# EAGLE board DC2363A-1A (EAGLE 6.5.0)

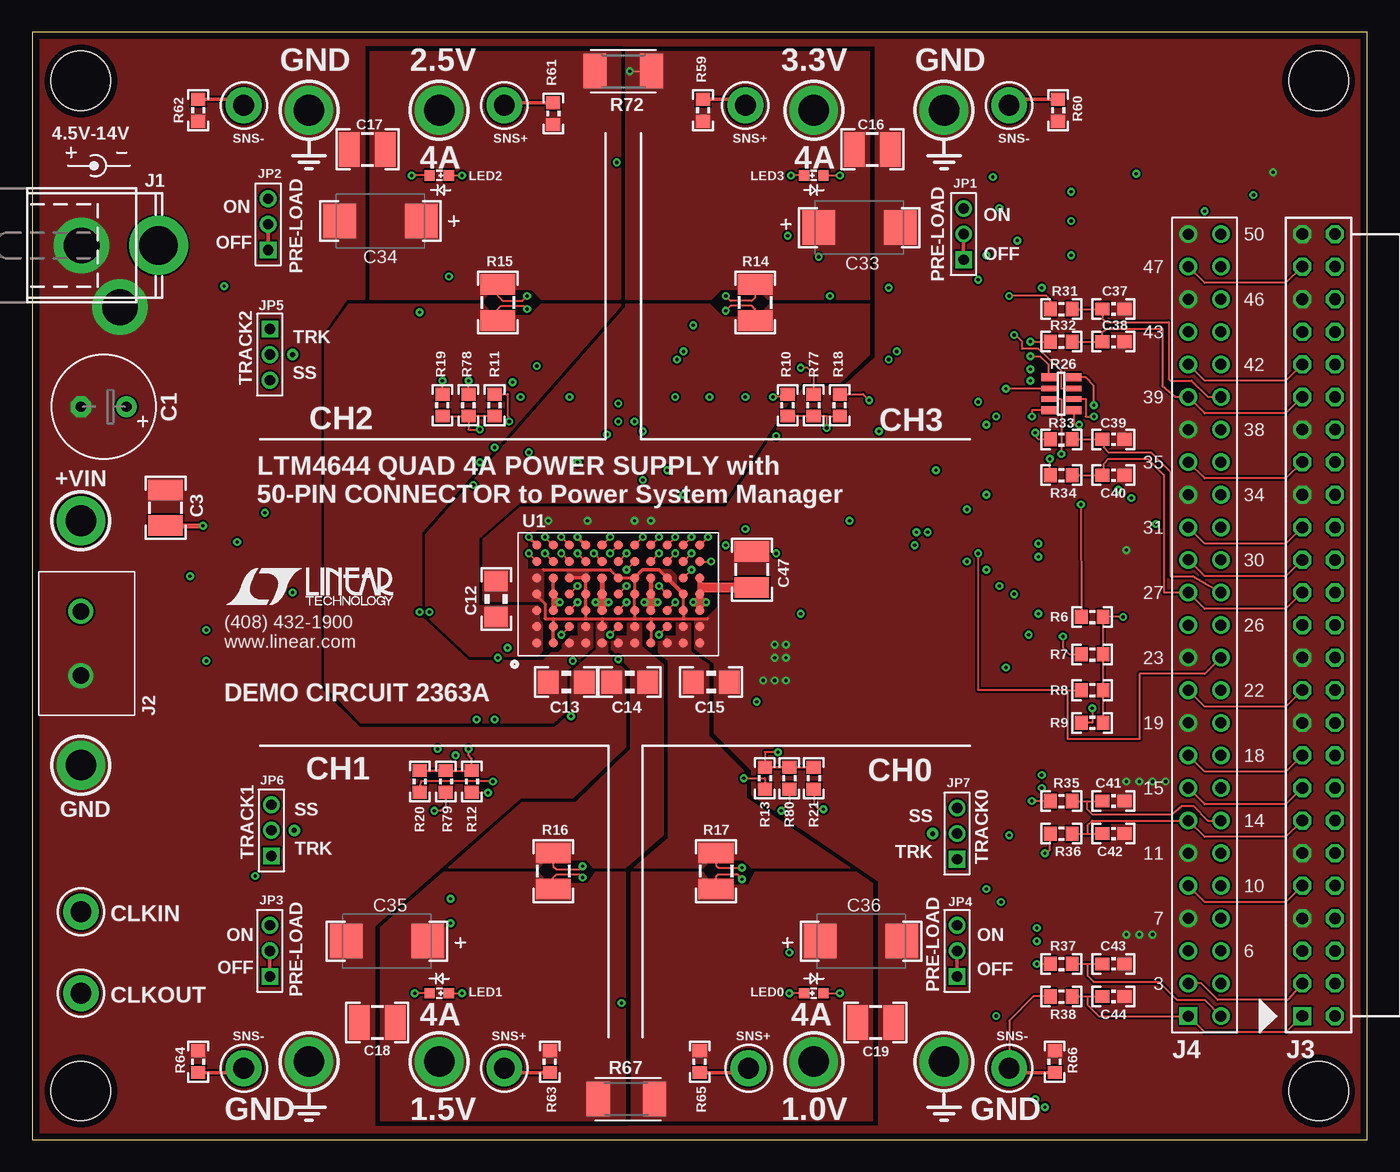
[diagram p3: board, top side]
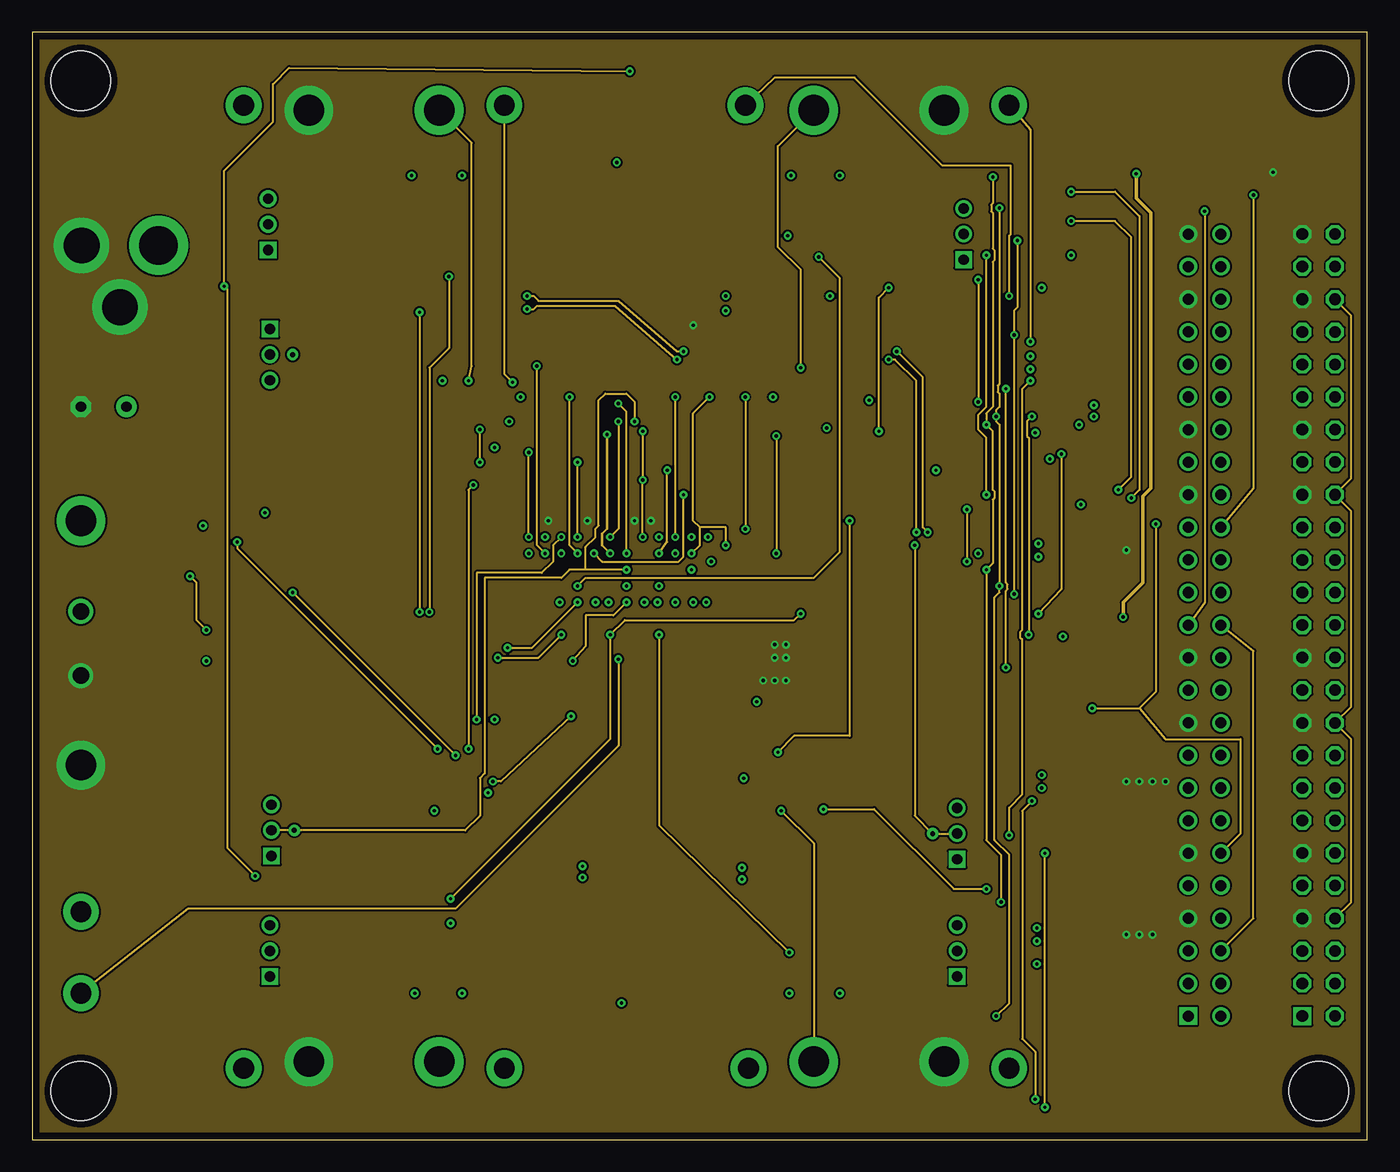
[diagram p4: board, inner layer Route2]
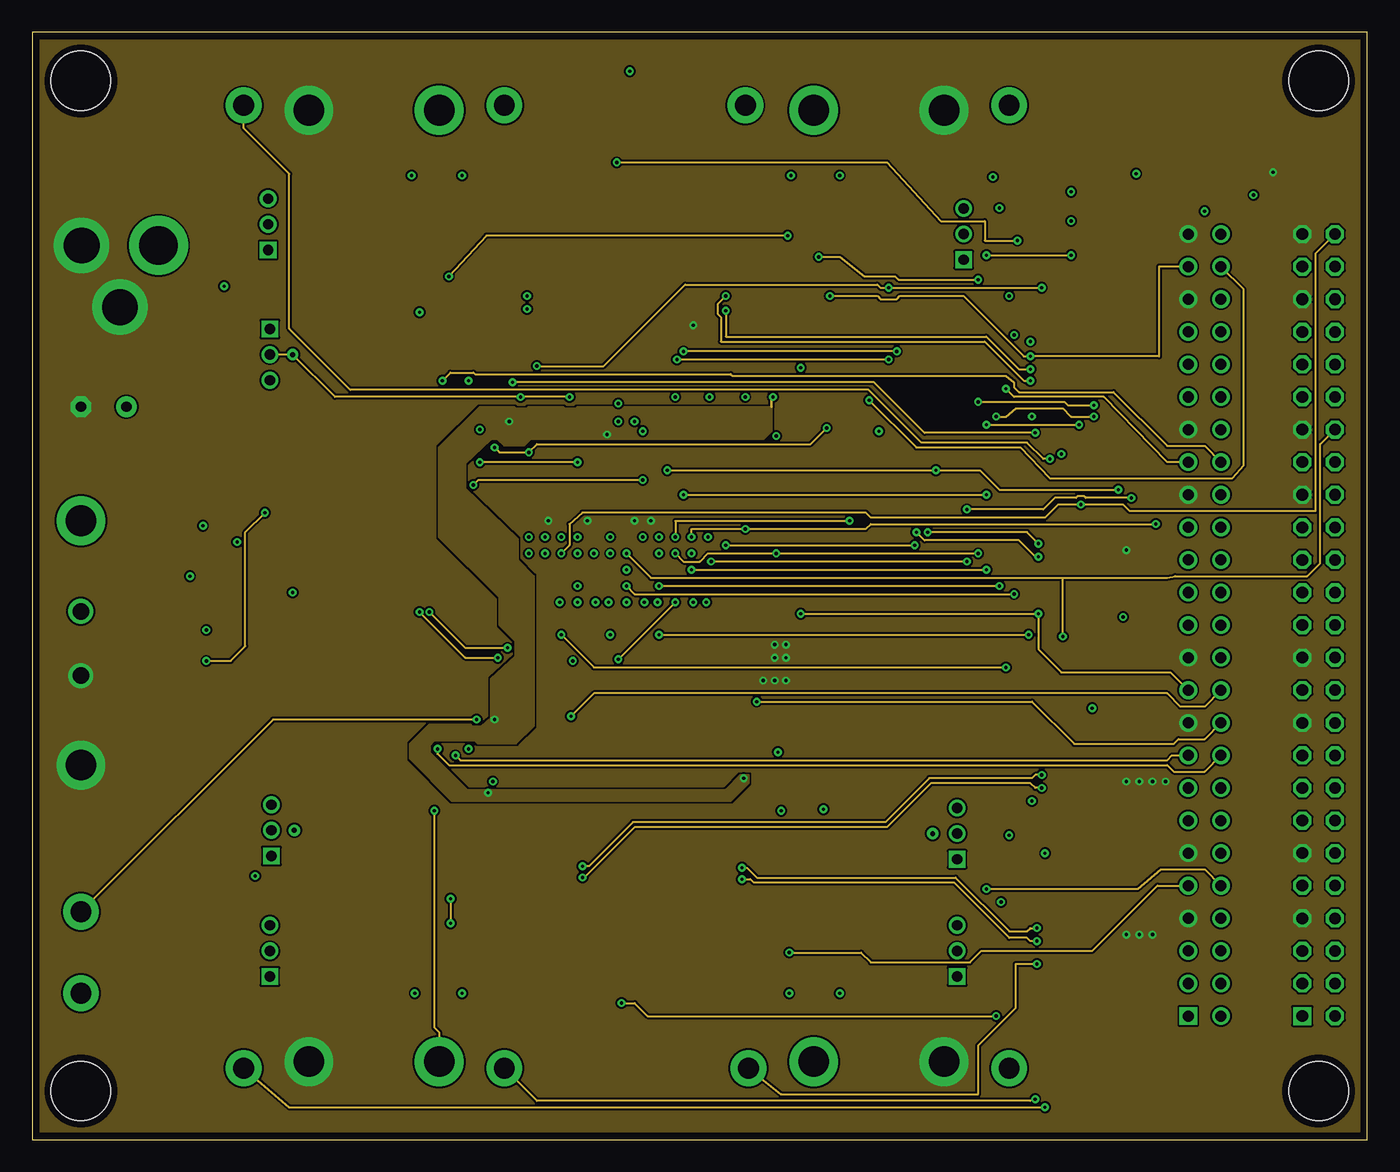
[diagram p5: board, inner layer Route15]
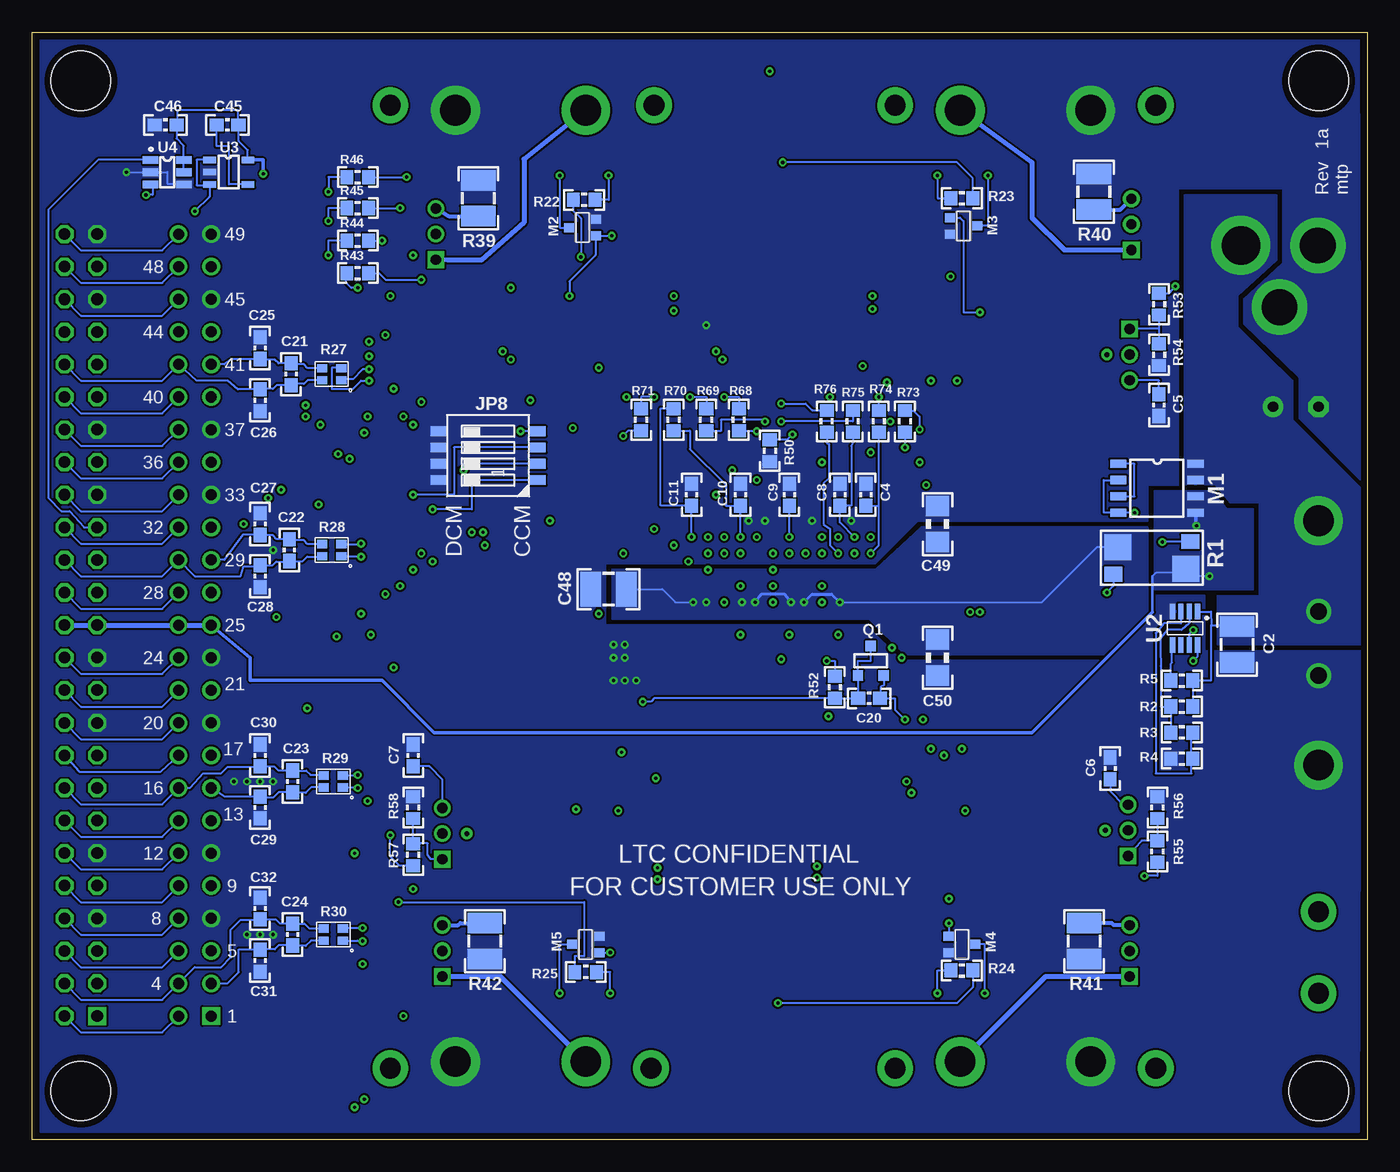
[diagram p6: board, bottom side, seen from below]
Size 104.14 x 86.36 mm. Coordinates in mm from the lower left corner, seen from the top.
Outline: 0,0 104.14,0 104.14,86.36 0,86.36 0,0
Copper layers (1*2+15*16): Top 0.07mm / dielectric 0.2mm / Route2 0.035mm / dielectric 1mm / Route15 0.035mm / dielectric 0.2mm / Bottom 0.07mm
Design rules "default *": minimum track width 6mil, minimum drill 10mil, track to track 6mil, track to pad 6mil, pad to pad 6mil, via to via 6mil, smd to smd 6mil, copper to edge 20mil, drill to drill 20mil, minimum pad ring 10mil, minimum via ring 7mil, stop-mask expansion 4mil, vias tented up to drill 16mil, thermal gap 0mil
Holes 4.65 mm at 3.81,3.81 3.81,82.55 100.33,82.55 100.33,3.81

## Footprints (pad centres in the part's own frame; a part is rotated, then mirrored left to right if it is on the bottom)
E3,5-8 = drill 0.813 pad 1.6: + -1.778,0 | drill 0.813 pad 1.6 octagon: - 1.778,0
C1210_BOX = smd 1.6 x 2.7: 1 -1.4,0; 2 1.4,0
C0603_BOX = smd 1.1 x 1: 1 -0.85,0; 2 0.85,0
C1206_BOX = smd 1.6 x 1.8: 1 -1.4,0; 2 1.4,0
D/7343-31R = smd 2.55 x 2.7: + 3.175,0; - -3.175,0
PJ-002A = drill 3 pad 4.6: 1 3,0 | drill 2.8 pad 4.3: 2 -3,0; 3 0,-4.8
691102710002 = drill 1.3: 1 -5,0; 2 0,0
PINHEAD_2X25_MALE = drill 0.9 square: 1 -1.27,-30.48 | drill 0.9 octagon: 2 1.27,-30.48; 3 -1.27,-27.94; 4 1.27,-27.94; 5 -1.27,-25.4; 6 1.27,-25.4; 7 -1.27,-22.86; 8 1.27,-22.86; 9 -1.27,-20.32; 10 1.27,-20.32; 11 -1.27,-17.78; 12 1.27,-17.78; 13 -1.27,-15.24; 14 1.27,-15.24; 15 -1.27,-12.7; 16 1.27,-12.7; 17 -1.27,-10.16; 18 1.27,-10.16; 19 -1.27,-7.62; 20 1.27,-7.62; 21 -1.27,-5.08; 22 1.27,-5.08; 23 -1.27,-2.54; 24 1.27,-2.54; 25 -1.27,0; 26 1.27,0; 27 -1.27,2.54; 28 1.27,2.54; 29 -1.27,5.08; 30 1.27,5.08; 31 -1.27,7.62; 32 1.27,7.62; 33 -1.27,10.16; 34 1.27,10.16; 35 -1.27,12.7; 36 1.27,12.7; 37 -1.27,15.24; 38 1.27,15.24; 39 -1.27,17.78; 40 1.27,17.78; 41 -1.27,20.32; 42 1.27,20.32; 43 -1.27,22.86; 44 1.27,22.86; 45 -1.27,25.4; 46 1.27,25.4; 47 -1.27,27.94; 48 1.27,27.94; 49 -1.27,30.48; 50 1.27,30.48
PINHEAD_2X25_MALE_NO_SILK = drill 0.864 square: 1 -1.27,-30.48 | drill 0.864: 2 1.27,-30.48; 3 -1.27,-27.94; 4 1.27,-27.94; 5 -1.27,-25.4; 6 1.27,-25.4; 7 -1.27,-22.86; 8 1.27,-22.86; 9 -1.27,-20.32; 10 1.27,-20.32; 11 -1.27,-17.78; 12 1.27,-17.78; 13 -1.27,-15.24; 14 1.27,-15.24; 15 -1.27,-12.7; 16 1.27,-12.7; 17 -1.27,-10.16; 18 1.27,-10.16; 19 -1.27,-7.62; 20 1.27,-7.62; 21 -1.27,-5.08; 22 1.27,-5.08; 23 -1.27,-2.54; 24 1.27,-2.54; 25 -1.27,0; 26 1.27,0; 27 -1.27,2.54; 28 1.27,2.54; 29 -1.27,5.08; 30 1.27,5.08; 31 -1.27,7.62; 32 1.27,7.62; 33 -1.27,10.16; 34 1.27,10.16; 35 -1.27,12.7; 36 1.27,12.7; 37 -1.27,15.24; 38 1.27,15.24; 39 -1.27,17.78; 40 1.27,17.78; 41 -1.27,20.32; 42 1.27,20.32; 43 -1.27,22.86; 44 1.27,22.86; 45 -1.27,25.4; 46 1.27,25.4; 47 -1.27,27.94; 48 1.27,27.94; 49 -1.27,30.48; 50 1.27,30.48
1X03-2MM = drill 0.8 square: 1 -2,0 | drill 0.8: 2 0,0; 3 2,0
SMT_DIP_4 = smd 1.27 x 0.762: 1 -3.861,1.905; 2 -3.861,0.635; 3 -3.861,-0.635; 4 -3.861,-1.905; 5 3.861,-1.905; 6 3.861,-0.635; 7 3.861,0.635; 8 3.861,1.905
CHIPLED_0603 = smd 0.8 x 0.8: N 0,0.75; P 0,-0.75
SOIC-8 = smd 1.27 x 0.635: 1 -3.175,1.905; 2 -3.175,0.635; 3 -3.175,-0.635; 4 -3.175,-1.905; 5 2.857,-1.905; 6 2.857,-0.635; 7 2.857,0.635; 8 2.857,1.905
SOT-323 = smd 0.7 x 0.9: 1 -0.65,-1; 2 0.65,-1; 3 0,1
SOT-23 = smd 0.8 x 0.8: 1 -1,-1.143; 2 1,-1.143; 3 0,1.157
2512_SHUNT_5MOHM = smd 1.143 x 1.397: E1 1.27,-2.997; E2 -1.27,2.997 | smd 2.007 x 2.108: I1 -0.838,-2.642; I2 0.838,2.642
R0603_BOX = smd 1 x 1.1: 1 -0.85,0; 2 0.85,0
R1210_BOX = smd 1.6 x 2.7: 1 -1.4,0; 2 1.4,0
R_VISHAY_CRA06S = smd 1.15 x 0.63: R1_1 -0.975,1.295; R1_2 0.975,1.295; R4_1 -0.975,-1.295; R4_2 0.975,-1.295 | smd 1.15 x 0.44: R2_1 -0.975,0.4; R2_2 0.975,0.4; R3_1 -0.975,-0.4; R3_2 0.975,-0.4
R_ARRAY_2X_ACAS = smd 0.64 x 0.8: P$1 -0.47,-0.75; P$2 0.47,-0.75; P$3 0.47,0.75; P$4 -0.47,0.75
R2010 = smd 1.8 x 2.7: 1 -2.2,0; 2 2.2,0
TURRET_LARGE_2501 = drill 2.388 pad 3.81: TP 0,0
TURRET_SMALL_2308 = drill 1.626 pad 2.794: TP1 0,0
VIA = drill 0.381: 1 0,0
BGA77_1.27 = smd 0.71 x 0.71: A1 -3.81,6.35; A2 -2.54,6.35; A3 -1.27,6.35; A4 0,6.35; A5 1.27,6.35; A6 2.54,6.35; A7 3.81,6.35; B1 -3.81,5.08; B2 -2.54,5.08; B3 -1.27,5.08; B4 0,5.08; B5 1.27,5.08; B6 2.54,5.08; B7 3.81,5.08; C1 -3.81,3.81; C2 -2.54,3.81; C3 -1.27,3.81; C4 0,3.81; C5 1.27,3.81; C6 2.54,3.81; C7 3.81,3.81; D1 -3.81,2.54; D2 -2.54,2.54; D3 -1.27,2.54; D4 0,2.54; D5 1.27,2.54; D6 2.54,2.54; D7 3.81,2.54; E1 -3.81,1.27; E2 -2.54,1.27; E3 -1.27,1.27; E4 0,1.27; E5 1.27,1.27; E6 2.54,1.27; E7 3.81,1.27; F1 -3.81,0; F2 -2.54,0; F3 -1.27,0; F4 0,0; F5 1.27,0; F6 2.54,0; F7 3.81,0; G1 -3.81,-1.27; G2 -2.54,-1.27; G3 -1.27,-1.27; G4 0,-1.27; G5 1.27,-1.27; G6 2.54,-1.27; G7 3.81,-1.27; H1 -3.81,-2.54; H2 -2.54,-2.54; H3 -1.27,-2.54; H4 0,-2.54; H5 1.27,-2.54; H6 2.54,-2.54; H7 3.81,-2.54; J1 -3.81,-3.81; J2 -2.54,-3.81; J3 -1.27,-3.81; J4 0,-3.81; J5 1.27,-3.81; J6 2.54,-3.81; J7 3.81,-3.81; K1 -3.81,-5.08; K2 -2.54,-5.08; K3 -1.27,-5.08; K4 0,-5.08; K5 1.27,-5.08; K6 2.54,-5.08; K7 3.81,-5.08; L1 -3.81,-6.35; L2 -2.54,-6.35; L3 -1.27,-6.35; L4 0,-6.35; L5 1.27,-6.35; L6 2.54,-6.35; L7 3.81,-6.35
TSOT-23-8 = smd 0.4 x 1.22: 1 -0.975,-1.31; 2 -0.325,-1.31; 3 0.325,-1.31; 4 0.975,-1.31; 5 0.975,1.31; 6 0.325,1.31; 7 -0.325,1.31; 8 -0.975,1.31
SOT-23-5 = smd 1 x 0.5: 1 -1.649,0.95; 2 -1.649,0; 3 -1.649,-0.95; 4 1.333,-0.95; 5 1.333,0.95
SOT-23-6 = smd 1.2 x 0.6: 1 -1.3,0.95; 2 -1.3,0; 3 -1.3,-0.95; 4 1.3,-0.95; 5 1.3,0; 6 1.3,0.95

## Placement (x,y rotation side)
C1  220uF/20V  [E3,5-8]  5.59,57.15 180 top
C2  22uF/25V  [C1210_BOX]  10.16,38.61 270 bottom
C3  22uF/25V  [C1210_BOX]  10.41,49.28 90 top
C4  10n  [C0603_BOX]  39.12,50.29 90 bottom
C5  10n  [C0603_BOX]  16.26,57.28 270 bottom
C6  10n  [C0603_BOX]  20.07,28.96 90 bottom
C7  10n  [C0603_BOX]  74.42,29.97 90 bottom
C8  OPT  [C0603_BOX]  41.15,50.29 90 bottom
C9  OPT  [C0603_BOX]  45.09,50.29 90 bottom
C10  OPT  [C0603_BOX]  48.9,50.29 90 bottom
C11  OPT  [C0603_BOX]  52.7,50.29 90 bottom
C12  47uF/10V  [C1206_BOX]  36.2,42.16 90 top
C13  47uF/10V  [C1206_BOX]  41.66,35.69 0 top
C14  47uF/10V  [C1206_BOX]  46.61,35.69 180 top
C15  47uF/10V  [C1206_BOX]  52.96,35.69 0 top
C16  22uF/10V  [C1210_BOX]  65.53,77.22 0 top
C17  22uF/10V  [C1210_BOX]  26.16,77.22 180 top
C18  22uF/10V  [C1210_BOX]  26.92,9.14 180 top
C19  22uF/10V  [C1210_BOX]  65.79,9.14 0 top
C20  100n  [C0603_BOX]  38.86,34.42 0 bottom
C21  10n  [C0603_BOX]  83.95,59.69 90 bottom
C22  10n  [C0603_BOX]  84.07,45.97 90 bottom
C23  10n  [C0603_BOX]  83.82,27.94 270 bottom
C24  10n  [C0603_BOX]  83.82,16 270 bottom
C25  OPT  [C0603_BOX]  86.36,61.72 270 bottom
C26  OPT  [C0603_BOX]  86.36,57.66 90 bottom
C27  OPT  [C0603_BOX]  86.36,48.01 270 bottom
C28  OPT  [C0603_BOX]  86.36,43.94 90 bottom
C29  OPT  [C0603_BOX]  86.36,25.91 90 bottom
C30  OPT  [C0603_BOX]  86.36,29.97 270 bottom
C31  OPT  [C0603_BOX]  86.36,13.97 90 bottom
C32  OPT  [C0603_BOX]  86.36,18.03 270 bottom
C33  330uF  [D/7343-31R]  64.52,71.12 180 top
C34  330uF  [D/7343-31R]  27.18,71.63 0 top
C35  330uF  [D/7343-31R]  27.69,15.49 0 top
C36  330uF  [D/7343-31R]  64.64,15.49 180 top
C37  10n  [C0603_BOX]  84.33,64.77 0 top
C38  10n  [C0603_BOX]  84.33,62.23 0 top
C39  10n  [C0603_BOX]  84.33,54.61 0 top
C40  10n  [C0603_BOX]  84.33,51.82 0 top
C41  10n  [C0603_BOX]  84.33,26.42 0 top
C42  10n  [C0603_BOX]  84.33,23.88 0 top
C43  10n  [C0603_BOX]  84.33,13.72 0 top
C44  10n  [C0603_BOX]  84.33,11.18 0 top
C45  10nF  [C0603_BOX]  88.9,79.12 180 bottom
C46  1uF  [C0603_BOX]  93.73,79.12 180 bottom
C47  22uF/25V  [C1210_BOX]  56.13,44.45 90 top
C48  22uF/25V  [C1210_BOX]  59.18,42.93 180 bottom
C49  22uF/25V  [C1206_BOX]  33.53,48.01 90 bottom
C50  22uF/25V  [C1206_BOX]  33.53,37.59 270 bottom
DRILEGEND  [DRILEGEND]  not placed on the board
J1  PJ-002A  [PJ-002A]  6.86,69.72 0 top
J2  691102710002  [691102710002]  3.81,36.2 270 top
J3  CONN_2X25_MALE  [PINHEAD_2X25_MALE]  100.33,40.13 0 top
J4  CONN_2X25_MALE_NO_SILK  [PINHEAD_2X25_MALE_NO_SILK]  91.44,40.13 0 top
JP1  PINHD-1X3-2MM  [1X03-2MM]  72.64,70.61 90 top
JP2  PINHD-1X3-2MM  [1X03-2MM]  18.41,71.37 90 top
JP3  PINHD-1X3-2MM  [1X03-2MM]  18.54,14.73 90 top
JP4  PINHD-1X3-2MM  [1X03-2MM]  72.14,14.73 90 top
JP5  PINHD-1X3-2MM  [1X03-2MM]  18.54,61.21 270 top
JP6  PINHD-1X3-2MM  [1X03-2MM]  18.67,24.13 90 top
JP7  PINHD-1X3-2MM  [1X03-2MM]  72.14,23.88 90 top
JP8  TDA04H0SK1  [SMT_DIP_4]  68.58,53.34 180 bottom
LED0  LED-0603  [CHIPLED_0603]  60.96,11.43 270 top
LED1  LED-0603  [CHIPLED_0603]  31.75,11.43 90 top
LED2  LED-0603  [CHIPLED_0603]  31.75,75.18 90 top
LED3  LED-0603  [CHIPLED_0603]  60.96,75.18 270 top
M1  SI4946BEY  [SOIC-8]  16.26,50.8 0 bottom
M2  DMG1012  [SOT-323]  61.21,71.12 90 bottom
M3  DMG1012  [SOT-323]  31.5,71.25 270 bottom
M4  DMG1012  [SOT-323]  31.62,15.24 270 bottom
M5  DMG1012  [SOT-323]  60.96,15.24 90 bottom
Q1  TEMP SENSE  [SOT-23]  38.73,37.34 0 bottom
R1  10m  [2512_SHUNT_5MOHM]  16.81,45.36 270 bottom
R2  2.1M  [R0603_BOX]  14.48,33.78 0 bottom
R3  221k  [R0603_BOX]  14.48,31.75 180 bottom
R4  80.6k  [R0603_BOX]  14.48,29.72 0 bottom
R5  100k  [R0603_BOX]  14.48,35.81 0 bottom
R6  49.9k  [R0603_BOX]  82.68,40.77 0 top
R7  49.9k  [R0603_BOX]  82.68,37.85 0 top
R8  49.9k  [R0603_BOX]  82.68,35.05 0 top
R9  49.9k  [R0603_BOX]  82.68,32.51 0 top
R10  1.21k  [R0603_BOX]  58.93,57.28 270 top
R11  1.74k  [R0603_BOX]  36.07,57.28 270 top
R12  3.65k  [R0603_BOX]  34.29,27.94 90 top
R13  8.25k  [R0603_BOX]  57.15,28.19 90 top
R14  10m  [R1210_BOX]  56.39,65.28 90 top
R15  10m  [R1210_BOX]  36.32,65.28 90 top
R16  10m  [R1210_BOX]  40.64,20.95 270 top
R17  10m  [R1210_BOX]  53.34,20.95 270 top
R18  6.81k  [R0603_BOX]  62.99,57.28 270 top
R19  8.25k  [R0603_BOX]  32,57.28 270 top
R20  14.3k  [R0603_BOX]  30.23,27.94 90 top
R21  20.5k  [R0603_BOX]  60.96,28.19 90 top
R22  2k  [R0603_BOX]  61.09,73.28 180 bottom
R23  2k  [R0603_BOX]  31.62,73.41 0 bottom
R24  2k  [R0603_BOX]  31.62,13.21 0 bottom
R25  2k  [R0603_BOX]  60.96,13.08 180 bottom
R26  R_ARRAY_4X_CRA06S  [R_VISHAY_CRA06S]  80.26,58.17 0 top
R27  R_ARRAY_2X_ACAS0606  [R_ARRAY_2X_ACAS]  80.77,59.69 90 bottom
R28  R_ARRAY_2X_ACAS0606  [R_ARRAY_2X_ACAS]  80.77,45.97 90 bottom
R29  R_ARRAY_2X_ACAS0606  [R_ARRAY_2X_ACAS]  80.64,27.94 90 bottom
R30  R_ARRAY_2X_ACAS0606  [R_ARRAY_2X_ACAS]  80.64,16 90 bottom
R31  100  [R0603_BOX]  80.26,64.77 0 top
R32  100  [R0603_BOX]  80.26,62.23 0 top
R33  100  [R0603_BOX]  80.26,54.61 0 top
R34  100  [R0603_BOX]  80.26,51.82 0 top
R35  100  [R0603_BOX]  80.26,26.42 0 top
R36  100  [R0603_BOX]  80.26,23.88 0 top
R37  100  [R0603_BOX]  80.26,13.72 0 top
R38  100  [R0603_BOX]  80.26,11.18 0 top
R39  33R  [R1210_BOX]  69.34,73.41 270 bottom
R40  25R  [R1210_BOX]  21.34,73.91 270 bottom
R41  15R  [R1210_BOX]  22.1,15.49 90 bottom
R42  10R  [R1210_BOX]  68.83,15.49 90 bottom
R43  10k  [R0603_BOX]  78.74,67.56 0 bottom
R44  10k  [R0603_BOX]  78.74,70.1 0 bottom
R45  10k  [R0603_BOX]  78.74,72.64 0 bottom
R46  10k  [R0603_BOX]  78.74,75.06 0 bottom
R50  OPT  [R0603_BOX]  46.61,53.72 90 bottom
R52  OPT  [R0603_BOX]  41.53,35.28 270 bottom
R53  60.4k  [R0603_BOX]  16.26,65.15 90 bottom
R54  19.1k  [R0603_BOX]  16.26,61.21 90 bottom
R55  60.4k  [R0603_BOX]  16.38,22.48 270 bottom
R56  40.2k  [R0603_BOX]  16.38,25.91 270 bottom
R57  60.4k  [R0603_BOX]  74.42,22.23 270 bottom
R58  90.9k  [R0603_BOX]  74.42,25.91 270 bottom
R59  1  [R0603_BOX]  52.32,80.26 90 top
R60  1  [R0603_BOX]  80.01,80.26 90 top
R61  1  [R0603_BOX]  40.64,80.01 90 top
R62  1  [R0603_BOX]  12.95,80.26 90 top
R63  1  [R0603_BOX]  40.39,6.1 270 top
R64  1  [R0603_BOX]  12.95,6.1 270 top
R65  1  [R0603_BOX]  52.07,6.1 270 top
R66  1  [R0603_BOX]  79.76,6.1 270 top
R67  DNI  [R2010]  46.35,3.17 180 top
R68  DNI  [R0603_BOX]  49.02,56.13 270 bottom
R69  DNI  [R0603_BOX]  51.56,56.13 270 bottom
R70  DNI  [R0603_BOX]  54.1,56.13 270 bottom
R71  DNI  [R0603_BOX]  56.64,56.13 270 bottom
R72  DNI  [R2010]  46.1,83.31 0 top
R73  DNI  [R0603_BOX]  36.07,56.01 270 bottom
R74  DNI  [R0603_BOX]  38.1,56.01 270 bottom
R75  DNI  [R0603_BOX]  40.13,56.01 270 bottom
R76  DNI  [R0603_BOX]  42.16,56.01 270 bottom
R77  6.04k  [R0603_BOX]  60.96,57.28 270 top
R78  6.04k  [R0603_BOX]  34.04,57.28 270 top
R79  6.04k  [R0603_BOX]  32.26,27.94 90 top
R80  6.04k  [R0603_BOX]  59.05,28.19 90 top
TP1  TURRET_LARGE_2501  [TURRET_LARGE_2501]  3.81,48.26 0 top
TP2  TURRET_LARGE_2501  [TURRET_LARGE_2501]  3.81,29.21 0 top
TP3  TURRET_LARGE_2501  [TURRET_LARGE_2501]  60.96,80.26 0 top
TP4  TURRET_LARGE_2501  [TURRET_LARGE_2501]  21.59,6.1 0 top
TP5  TURRET_LARGE_2501  [TURRET_LARGE_2501]  31.75,80.26 0 top
TP6  TURRET_LARGE_2501  [TURRET_LARGE_2501]  71.12,6.1 0 top
TP7  TURRET_LARGE_2501  [TURRET_LARGE_2501]  31.75,6.1 0 top
TP8  TURRET_LARGE_2501  [TURRET_LARGE_2501]  71.12,80.26 0 top
TP9  TURRET_LARGE_2501  [TURRET_LARGE_2501]  60.96,6.1 0 top
TP10  TURRET_LARGE_2501  [TURRET_LARGE_2501]  21.59,80.26 0 top
TP11  TURRET_SMALL_2308TP  [TURRET_SMALL_2308]  3.81,17.78 0 top
TP12  TURRET_SMALL_2308TP  [TURRET_SMALL_2308]  3.81,11.43 0 top
TP14  TESTPOINT_SMDVIA  [VIA]  20.32,61.21 0 top
TP15  TESTPOINT_SMDVIA  [VIA]  20.45,24.13 0 top
TP16  TESTPOINT_SMDVIA  [VIA]  70.23,23.88 0 top
TP17  TURRET_SMALL_2308TP  [TURRET_SMALL_2308]  55.63,80.64 0 top
TP18  TURRET_SMALL_2308TP  [TURRET_SMALL_2308]  76.2,80.64 0 top
TP19  TURRET_SMALL_2308TP  [TURRET_SMALL_2308]  36.83,80.64 0 top
TP20  TURRET_SMALL_2308TP  [TURRET_SMALL_2308]  16.51,80.64 0 top
TP21  TURRET_SMALL_2308TP  [TURRET_SMALL_2308]  36.83,5.59 0 top
TP22  TURRET_SMALL_2308TP  [TURRET_SMALL_2308]  16.51,5.59 0 top
TP23  TURRET_SMALL_2308TP  [TURRET_SMALL_2308]  55.88,5.59 0 top
TP24  TURRET_SMALL_2308TP  [TURRET_SMALL_2308]  76.2,5.59 0 top
U1  LTM4644  [BGA77_1.27]  45.72,42.55 90 top
U2  LTC4365  [TSOT-23-8]  14.22,39.88 180 bottom
U3  LT1761ES5-3.3  [SOT-23-5]  88.65,75.44 0 bottom
U4  24LC025  [SOT-23-6]  93.6,75.44 0 bottom
U$4  [LT_LOGO_MED_WITH_TEXT]  14.99,41.66 0 top
U$5  [DC2363_FRAME]  not placed on the board

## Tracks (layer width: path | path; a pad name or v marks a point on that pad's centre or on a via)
3P3V  (via drill 0.25, 0.25 pad 0.61)
  Top 0.152: R9.2 R8.2 R7.2 R6.2 v85.09,40.77
  Route2 0.254: v86.11,75.31 86.11,73.41 87.25,72.26 87.25,50.8 86.61,50.16 86.61,43.43 85.09,41.91 v85.09,40.77
  Bottom 0.152: U3.5 87.31,77.15 88.01,77.85 88.01,79.08 C45.1 88.05,80.26 92.84,80.26 92.84,79.12 C46.1 92.88,78.07 92.3,77.49 U4.6 U4.5
  Bottom 0.254: v86.11,75.31 86.11,76.39 U3.5
+VIN
  Bottom 0.152: U2.1 12.21,41.19 12.19,40.13 | 12.19,40.13 10.16,40.13 C2.1 | R2.2 R5.2 12.19,35.81 12.19,40.13
  pour Bottom: 0.51,38.61 11.68,38.61 11.68,42.42 8.38,42.42 8.38,49.66 10.67,49.66 11.81,51.05 14.22,51.05 14.22,73.66 7.11,73.66 7.11,68.58 10.16,65.79 10.16,63.37 5.84,59.18 5.84,56.13 0.51,50.8
AGND  (via drill 0.25)
  Top 0.152: R12.1 35.52,27.09 v35.56,27.05 | v55.5,28.19 57.15,28.19 R13.1 | R11.1 37.08,58.13 37.08,56.52 v37.21,56.01 | R10.1 58.71,57.91 v57.78,57.91
  Top 0.203: U1.F7 v45.09,45.72
  Route2 0.203: v45.09,45.72 44.45,46.35 44.45,47.24 44.83,47.62 v44.83,54.99
  Route15 0.152: v57.78,57.91 57.66,57.78 | v36.07,32.77 35.94,32.77 35.81,32.89
  Route15 0.203: 57.66,57.78 57.66,57.15
  Bottom 0.152: R50.2 46.57,54.61 45.21,54.61 v44.83,54.99 | Q1.2 37.72,35.43 37.97,35.31 37.97,34.46 C20.2 36.83,34.42 36.83,33.53 v36.07,32.77
  pour Route15: 57.66,57.15 57.66,55.24 57.02,54.61 38.86,54.61 38.35,54.1 36.83,54.1 36.32,54.61 35.81,54.61 33.78,52.7 33.78,50.8 37.85,46.86 37.85,45.21 39.12,43.94 39.12,32.26 37.72,30.86 34.8,30.86 34.54,31.11 31.37,31.11 30.99,30.73 30.99,30.23 33.91,27.3 54.1,27.3 55.24,28.45 55.88,28.45 55.88,27.81 54.48,26.42 32.77,26.42 29.46,29.72 29.46,30.86 30.99,32.38 34.16,32.38 34.29,32.26 35.05,32.26 35.81,32.89 35.81,35.94 37.72,37.72 37.72,38.86 36.45,40.13 36.45,42.29 31.75,46.99 31.75,53.98 34.92,57.15 37.59,57.15 37.72,57.02 38.61,57.02 38.73,57.15 41.4,57.15 41.53,57.02 42.42,57.02 42.55,57.15
AUX_SCL
  Top 0.152: J3.31 97.79,46.48 91.44,46.48 J4.31
  Bottom 0.152: U4.1 99,76.39 102.87,72.52 102.87,50.04 101.85,49.02 101.22,49.02 100.08,47.75 J3.31
AUX_SDA  (via drill 0.25 pad 0.61)
  Route2 0.152: v95.25,73.66 95.25,50.8 J4.32
  Bottom 0.152: J3.32 100.33,46.48 93.98,46.48 J4.32 | U4.3 94.74,74.42 94.74,73.66 v95.25,73.66
CLKIN  (via drill 0.25)
  Top 0.152: U1.C7 v41.27,46.99
  Route2 0.152: v41.27,46.99 40.64,46.35 40.64,45.09 39.75,44.2 34.67,44.2 v34.67,32.77
  Route15 0.152: v34.67,32.77 18.8,32.77 TP11.TP1
CLKOUT  (via drill 0.25, 0.25 pad 0.61)
  Top 0.152: U1.J3 v50.16,41.91
  Route2 0.152: v45.72,37.47 45.72,30.73 33.02,18.03 12.19,18.03 TP12.TP1
  Route15 0.152: v50.16,41.91 v45.72,37.47
GND  (via drill 0.25)
  Top 0.229: 39.88,44.45 45.09,44.45 U1.F5 U1.G5 U1.G4 U1.G3 46.99,40.64 48.26,40.64 U1.H2 U1.H1 | U1.K4 U1.K3 50.8,40.64 | U1.D3 43.18,40.64 44.45,40.64 U1.E2 | U1.A4 39.37,42.42 40.01,41.78 40.01,40.64 40.64,40.64 | 40.64,40.64 U1.B2 | 40.64,40.64 50.8,40.64 | 50.8,40.64 52.7,40.64
  Top 0.254: U1.D3 U1.D4 U1.D5 U1.C5 | U1.B1 U1.B2 | U1.G5 47.62,44.45 48.9,44.45 U1.J5
  Top 0.305: U1.K4 U1.J5
  Bottom 0.152: v96.77,75.44 U4.2 93.6,75.44 93.6,74.55 92.3,74.55 U4.4
  other vias: 85.34,27.94 86.36,27.94 87.38,27.94 88.39,27.94 85.34,16 86.36,16 87.38,16 85.34,45.97 40.26,48.26 43.31,48.26 46.99,48.26 48.26,48.26 51.56,63.5 57.02,35.81 57.91,35.81 57.91,37.59 57.91,38.61 58.8,38.61 58.8,37.59 58.8,35.81
  pour Top: 39.88,42.04 39.88,44.45 38.61,44.45 38.61,46.86 39.37,47.62 53.59,47.62 53.59,41.66 52.58,40.64 51.69,40.64 51.69,38.35 52.32,37.85 53.21,37.21 53.21,31.75 56.13,28.83 56.13,26.92 66.04,20.19 66.04,1.02 46.48,1.02 46.48,0.51 103.63,0.51 103.63,85.85 46.1,85.85 46.1,85.34 65.79,85.34 65.79,60.96 63.25,58.67 60.2,58.67 54.1,49.28 38.1,49.28 35.18,46.74 35.18,42.04
  pour Top (rank 2): 44.07,40.34 44.83,40.34 44.83,39.88 44.58,39.62 44.58,39.12 44.83,38.86 44.83,37.97 46.23,36.58 46.23,30.61 42.16,26.67 38.1,26.67 26.67,16.64 26.67,1.02 46.48,1.02 46.48,0.51 0.51,0.51 0.51,85.85 46.1,85.85 46.1,85.34 25.91,85.34 25.91,65.53 24.51,65.53 22.48,62.61 22.48,35.18 25.53,32.13 40.77,32.13 42.04,33.27 42.04,36.45 44.07,38.23
  pour Bottom: 12.7,38.1 12.7,42.42 16.51,42.42 16.51,41.02 20.32,37.34 36.32,37.34 39.12,40.13 59.44,40.13 59.44,44.96 38.35,44.96 35.05,48.26 17.14,48.26 17.14,51.05 14.73,51.05 14.73,74.17 6.6,74.17 6.6,68.33 9.65,65.53 9.65,63.63 5.33,59.44 5.33,56.26 0.51,51.44 0.64,85.72 103.5,85.72 103.5,0.64 0.64,0.64 0.51,38.1
  pour Route2: 0.64,85.72 103.5,85.72 103.5,0.64 0.64,0.64
  pour Route15 (rank 2): 0.64,85.72 103.5,85.72 103.5,0.64 0.64,0.64
  pour Top: 41.78,44.45 43.31,44.45 43.31,43.81 41.78,43.81
  pour Top: 48.9,44.45 49.78,44.45 50.16,44.07 50.16,43.18
IIN_SNSM  (via drill 0.25 pad 0.61)
  Top 0.152: J3.17 97.79,28.7 91.44,28.7 J4.17
  Route2 0.152: v20.32,42.67 v33.02,29.97
  Route15 0.152: v33.02,29.97 33.4,29.59 88.52,29.59 88.9,29.97 J4.17
  Bottom 0.152: R1.E1 19.81,43.18 v20.32,42.67
IIN_SNSP  (via drill 0.25 pad 0.61)
  Route2 0.152: v16,46.61 16,46.1 v31.62,30.48
  Route15 0.152: v31.62,30.48 31.62,30.1 32.51,29.21 88.52,29.21 89.03,28.7 91.44,28.7 J4.18
  Bottom 0.152: J3.18 100.46,28.7 94.11,28.7 J4.18 | R1.E2 15.98,46.63 v16,46.61
INT1  (via drill 0.25, 0.25 pad 0.61)
  Top 0.152: v82.8,57.28 82.8,58.8 82.17,59.44 81.24,59.44 R26.R1_2 | U1.C4 v42.55,43.18
  Route2 0.152: v73.79,67.06 v73.79,57.53 | v42.55,43.18 43.18,43.81 60.96,43.81 62.99,45.85 62.99,67.18 v61.34,68.83
  Route15 0.152: v61.34,68.83 62.99,68.83 64.9,67.31 67.31,67.31 67.56,67.06 v73.79,67.06 | v73.79,57.53 80.52,57.53 80.77,57.28 v82.8,57.28
  Bottom 0.152: v61.34,68.83 61.34,71.84 61.94,72.44 R22.2 | R43.2 77.09,67.56 76.58,67.06 v73.79,67.06
INT2  (via drill 0.25, 0.25 pad 0.61)
  Top 0.152: U1.F4 v46.35,43.18 | R26.R2_2 80.26,58.57 80.26,59.94 78.49,61.67 77.22,61.67 77.22,62.23 76.71,62.74 v76.58,62.74
  Route2 0.152: v76.83,70.1 76.83,64.9 76.58,64.64 v76.58,62.74 v76.58,42.55
  Route15 0.152: v46.35,43.18 46.99,42.55 v76.58,42.55 | v45.59,76.2 66.67,76.2 70.87,71.63 74.3,71.63 74.3,70.1 v76.83,70.1
  Bottom 0.152: R44.2 v76.83,70.1 | R23.2 30.77,74.97 32,76.2 v45.59,76.2
INT3  (via drill 0.25, 0.25 pad 0.61)
  Top 0.152: U1.J4 v48.9,43.18 | R26.R3_2 82.17,57.77 82.17,56.39 v82.8,56.39
  Route2 0.152: v75.44,72.64 75.44,58.93 75.31,58.8 75.31,58.29 75.44,58.17 75.44,57.15 75.18,56.9 v75.18,56.39 75.18,56.01 75.44,55.75 v75.44,43.18 75.44,42.67 75.06,42.29 75.06,23.37 76.2,22.23 76.2,10.67 v75.18,9.65
  Route15 0.152: v48.9,43.18 v75.44,43.18 | v45.97,10.67 46.99,10.67 48.01,9.65 v75.18,9.65 | v75.18,56.39 75.95,56.39 76.71,57.02 80.39,57.02 81.03,56.39 v82.8,56.39
  Bottom 0.152: R45.2 v75.44,72.64 | R24.2 30.77,11.9 32,10.67 v45.97,10.67
INT4  (via drill 0.25, 0.25 pad 0.61)
  Top 0.152: U1.K5 v51.44,44.45 | v81.66,55.75 81.28,55.75 81.28,56.83 R26.R4_2
  Route2 0.152: v74.93,75.06 74.93,73.03 74.8,72.9 74.8,72.39 74.93,72.26 74.93,69.47 75.06,69.34 75.06,68.58 74.93,68.45 74.93,57.15 74.42,56.64 v74.42,55.75 74.93,55.24 74.93,50.67 75.06,50.55 75.06,50.04 74.93,49.91 74.93,44.96 v74.42,44.45 74.42,23.37 75.56,22.23 v75.56,18.54
  Route15 0.152: v51.44,44.45 v74.42,44.45 | v74.42,55.75 v81.66,55.75
  Bottom 0.152: R46.2 v74.93,75.06 | v75.56,18.54 61.09,18.54 61.09,14.35 61.81,14.35 R25.2
ISM0  (via drill 0.25)
  Top 0.152: v55.37,20.32 arc-90 55.12,20.57 arc90 54.86,20.7 53.59,20.7 arc90 53.34,20.45 R17.2 | R80.1 59.05,26.29 v58.42,25.65
  Top 0.254: JP4.1 JP4.2
  Route2 0.152: TP9.TP 60.96,23.11 v58.42,25.65
  Route15 0.152: v55.37,20.32 56.01,20.32 56.26,20.07 71.88,20.07 76.2,15.75 77.6,15.75 77.85,15.49 v78.36,15.49
  Bottom 0.152: R30.P$1 78.78,15.53 v78.36,15.49
  Bottom 0.406: TP9.TP 67.6,12.73 JP4.1
  pour Top: 46.74,20.83 46.74,1.52 65.53,1.52 65.53,19.94 64.26,20.83 56.39,20.83 55.88,19.81 53.09,19.81 52.32,20.83
ISM1  (via drill 0.25)
  Top 0.152: v42.93,20.45 42.67,20.7 40.89,20.7 40.64,20.45 R16.2 | R79.1 32.26,26.04 31.88,25.65 v31.37,25.65
  Top 0.254: JP3.1 JP3.2
  Route15 0.152: v78.74,27.43 78.23,27.43 77.85,27.81 70.1,27.81 66.67,24.38 46.99,24.38 43.05,20.45 v42.93,20.45 | v31.37,25.65 31.37,8.76 31.75,8.38 TP7.TP
  Bottom 0.152: R29.P$1 78.78,27.47 v78.74,27.43
  Bottom 0.406: JP3.1 25.11,12.73 TP7.TP
  pour Top: 27.18,16.51 27.18,1.52 46.23,1.52 46.23,20.83 43.94,20.83 43.31,19.94 40.26,19.94 39.5,20.83 32.13,20.83
ISM2  (via drill 0.25)
  Top 0.152: v38.61,65.79 38.23,65.41 36.7,65.41 36.32,65.79 R15.2 | R78.1 v34.04,59.18
  Top 0.254: JP2.2 JP2.1
  Route2 0.152: v69.85,47.37 69.47,47.75 69.47,59.44 v67.44,61.47 | v38.61,65.79 39.12,65.79 39.5,65.41 45.72,65.41 50.29,61.47 v50.8,61.47 | v34.04,59.18 34.29,60.33 34.29,77.72 TP5.TP
  Route15 0.152: v78.49,46.48 77.6,47.37 v69.85,47.37 | v67.44,61.47 v50.8,61.47
  Bottom 0.152: R28.P$2 78.52,46.44 v78.49,46.48
  Bottom 0.406: TP5.TP 26.16,76.2 26.16,71.88 23.65,69.37 JP2.1
  pour Top: 26.42,65.53 26.42,84.84 45.85,84.84 45.85,65.53 39.75,65.53 38.99,66.29 35.94,66.29 35.18,65.53
ISM3  (via drill 0.25, 0.25 pad 0.61)
  Top 0.152: v46.61,83.31 R72.2 | v54.1,65.79 54.48,65.41 56.13,65.41 56.39,65.66 R14.2 | R77.1 60.96,59.69 60.45,60.2 v59.94,60.2
  Top 0.254: JP1.2 JP1.1
  Route2 0.152: v17.4,20.57 15.24,22.73 15.24,66.29 v14.99,66.55 14.99,75.56 18.8,79.38 18.8,82.3 20.07,83.57 v46.61,83.31 | v59.94,60.2 59.94,67.82 58.17,69.6 58.17,77.47 TP3.TP | v76.2,23.75 76.2,25.91 77.22,26.92 77.22,38.99 77.09,39.12 77.09,39.62 77.22,39.75 77.22,58.55 v77.85,59.18
  Route15 0.152: v54.1,65.79 53.47,65.15 53.47,64.39 53.72,64.14 53.72,62.23 74.3,62.23 77.34,59.18 v77.85,59.18
  Bottom 0.152: R55.2 16.38,20.57 v17.4,20.57 | R53.2 15.46,66 v14.99,66.55 | R27.P$2 80.01,60.17 80.77,60.17 80.77,58.55 79.12,58.55 78.49,59.18 v77.85,59.18 | R57.2 75.48,21.38 76.2,22.1 v76.2,23.75
  Bottom 0.406: TP3.TP 65.79,76.45 65.79,71.5 69.09,68.58 71.72,68.58 JP1.1
  pour Top: 46.35,65.53 46.35,84.84 65.28,84.84 65.28,65.53 57.4,65.53 56.64,66.29 53.72,66.29 52.96,65.53
ISNSM_CH0
  Top 0.152: J3.3 97.92,10.92 92.46,10.92 91.19,12.19 J4.3
  Bottom 0.152: R30.P$4 82.39,15.53 82.8,15.11 83.78,15.11 C24.2 84.92,15.15 85.22,14.86 86.32,14.86 C31.2 86.4,14.86 88.01,14.86 88.01,13.08 88.9,12.19 J4.3
ISNSM_CH1
  Top 0.152: J3.15 97.79,26.16 91.44,26.16 J4.15
  Bottom 0.152: R29.P$4 82.39,27.47 82.8,27.05 83.78,27.05 C23.2 84.92,27.09 85.34,26.67 86.27,26.67 C29.2 89.11,26.76 J4.15
ISNSM_CH2
  Top 0.152: J3.29 97.79,43.94 91.44,43.94 J4.29
  Bottom 0.152: R28.P$3 82.64,46.44 82.93,46.74 83.99,46.74 C22.2 85.05,46.82 85.34,47.12 86.32,47.12 C27.2 87.72,47.16 89.15,45.21 J4.29
ISNSM_CH3
  Top 0.152: J3.41 97.79,59.18 91.44,59.18 J4.41
  Bottom 0.152: R27.P$3 82.64,60.16 82.93,60.45 83.86,60.45 C21.2 84.92,60.54 85.22,60.83 86.32,60.83 C25.2 88.56,60.87 89.15,60.45 J4.41
ISNSP_CH0
  Bottom 0.152: J3.4 100.33,10.92 93.98,10.92 J4.4 91.44,13.46 89.41,13.46 88.65,14.22 88.65,16.38 87.88,17.14 86.4,17.14 C32.2 85.13,17.18 84.84,16.89 83.86,16.89 C24.1 82.89,16.85 82.55,16.51 81.43,16.51 R30.P$3
ISNSP_CH1
  Bottom 0.152: J3.16 100.33,26.16 93.98,26.16 J4.16 91.82,27.43 90.81,28.57 89.41,28.57 88.9,29.08 86.4,29.08 C30.2 85.26,29.12 84.96,28.83 83.86,28.83 C23.1 82.77,28.79 82.42,28.45 81.43,28.45 R29.P$3
ISNSP_CH2
  Bottom 0.152: J3.30 100.33,43.94 93.98,43.94 J4.30 91.44,43.94 87.88,43.94 87.63,44.7 86.45,44.7 C28.2 85.38,44.79 85.09,45.09 84.11,45.09 C22.1 83.02,45.12 82.68,45.47 81.56,45.47 R28.P$4
ISNSP_CH3
  Bottom 0.152: J3.42 100.33,59.18 93.98,59.18 J4.42 91.31,59.18 88.9,59.18 88.1,58.51 C26.2 86.32,58.55 85.34,58.55 85.05,58.84 C21.1 83.86,58.93 82.93,58.93 82.64,59.22 R27.P$4
ISP0  (via drill 0.25)
  Top 0.152: v55.37,21.21 53.59,21.21 arc-90 53.34,21.46 R17.1
  Route15 0.152: v55.37,21.21 55.75,21.21 56.52,20.45 72.01,20.45 76.2,16.26 77.6,16.26 77.85,16.51 v78.36,16.51
  Bottom 0.152: v78.36,16.51 79.86,16.51 R30.P$2
  pour Top: 50.29,40.39 51.31,40.39 51.31,38.1 52.07,37.47 52.7,37.08 52.7,31.5 55.63,28.57 55.63,26.67 60.33,23.5 63.75,21.21 56.13,21.21 55.5,21.84 52.96,21.84 52.32,21.21 46.99,21.21 49.66,23.5 49.66,37.34 48.9,37.97 48.9,38.86 49.28,39.24 50.29,39.24
ISP1  (via drill 0.25)
  Top 0.152: v42.93,21.34 42.67,21.08 40.89,21.08 40.64,21.34 R16.1
  Route15 0.152: v78.74,28.45 78.23,28.45 77.98,28.19 69.98,28.19 66.55,24.77 46.86,24.77 43.43,21.34 v42.93,21.34
  Bottom 0.152: R29.P$2 78.78,28.41 v78.74,28.45
  pour Top: 46.48,40.34 47.5,40.34 47.5,38.48 49.15,37.08 49.15,23.75 46.23,21.21 43.81,21.21 43.31,21.84 40.13,21.84 39.5,21.21 32.51,21.21 38.23,26.29 42.42,26.29 46.74,30.48 46.74,36.7 45.21,38.23 45.21,38.99 45.47,39.24 46.48,39.24
ISP2  (via drill 0.25)
  Top 0.152: v38.61,64.77 38.35,65.02 36.58,65.02 36.32,64.77 R15.1
  Route2 0.152: v68.96,47.37 68.96,59.18 67.31,60.83 v66.8,60.83 | v38.61,64.77 39.12,64.77 39.37,65.02 45.47,65.02 v50.29,60.83
  Route15 0.152: v78.49,45.47 78.23,45.47 76.96,46.74 69.6,46.74 v68.96,47.37 | v66.8,60.83 v50.29,60.83
  Bottom 0.152: R28.P$1 78.52,45.5 v78.49,45.47
  pour Top: 42.67,40.34 43.69,40.34 43.69,38.35 41.66,36.58 41.66,33.4 40.64,32.51 25.65,32.51 22.86,35.43 22.86,62.48 24.77,65.15 35.18,65.15 36.07,64.26 38.86,64.26 39.75,65.15 45.85,65.15 45.85,65.02 30.35,47.37 30.35,40.77 34.04,37.34 39.88,37.34 40.51,37.97 41.05,37.97 41.4,38.33 41.4,38.61 42.04,39.24 42.67,39.24
ISP3  (via drill 0.25)
  Top 0.152: R14.1 56.39,64.77 56.13,65.02 54.48,65.02 v54.1,64.64
  Route15 0.152: v54.1,64.64 54.1,62.61 74.42,62.61 76.96,60.07 v77.85,60.07
  Bottom 0.152: v77.85,60.07 78.36,60.07 79.12,59.31 79.93,59.31 R27.P$1
  pour Top: 39.75,40.28 39.75,38.13 39.37,37.72 34.16,37.72 30.73,40.89 30.73,47.12 46.35,64.9 46.35,65.15 52.83,65.15 53.85,64.14 56.52,64.14 57.53,65.15 65.28,65.15 65.28,61.21 62.99,59.05 59.94,59.05 53.85,49.66 37.97,49.66 34.8,46.86 34.8,41.66 39.4,41.66 39.5,41.43 39.5,40.59
N$1  (via drill 0.25)
  Route15 0.152: v13.59,37.34 15.49,37.34 16.64,38.48 16.64,47.37 v18.16,48.9
  Bottom 0.152: U2.8 13.25,37.68 v13.59,37.34 | v18.16,48.9 M1.4 20.57,48.9 20.57,51.44 M1.2
N$2
  Bottom 0.152: M1.3 18.16,50.16 18.16,52.7 M1.1
N$5
  Bottom 0.152: R5.1 15.33,37.12 15.24,37.21 15.24,38.53 U2.5
N$6
  Bottom 0.152: U2.2 13.89,40.26 14.48,39.75 15.62,39.75 16.13,39.11 16.13,38.17 16.13,36.96 16.13,33.78 R2.1 R3.2
N$7
  Bottom 0.152: U2.3 14.55,40.26 15.88,40.26 16.51,39.5 16.51,28.57 13.72,28.57 13.72,29.72 | 13.72,29.72 R4.2 | 13.72,29.72 13.72,31.75 R3.1
N$9  (via drill 0.25)
  Top 0.152: U1.L7 v52.7,46.99
  Bottom 0.152: v52.7,46.99 C11.1 55.12,49.44 55.12,57.02 54.1,57.02 R70.1
N$10  (via drill 0.25)
  Top 0.152: U1.H7 v48.9,46.99
  Bottom 0.152: v48.9,46.99 C10.1 50.04,49.44 50.04,51.05 52.83,53.85 52.83,55.28 R70.2
N$11  (via drill 0.25, 0.25 pad 0.61)
  Top 0.152: U1.E7 v45.09,46.99
  Route2 0.152: v45.72,56.01 45.72,47.62 v45.09,46.99
  Bottom 0.152: v45.09,46.99 C9.1 | R75.1 40.13,56.01 v45.72,56.01
N$12  (via drill 0.25)
  Top 0.152: U1.B7 v40.01,46.99
  Bottom 0.152: v40.01,46.99 41.15,48.13 C8.1 40.26,49.44 40.26,54.1 40.13,54.36 R75.2
N$14
  Bottom 0.152: C5.1 16.26,59.21 JP5.3
N$16
  Bottom 0.152: C6.1 20.07,27.18 19.02,26.13 JP6.3
N$17  (via drill 0.25, 0.25 pad 0.61)
  Top 0.152: v61.98,55.5 61.98,56.43 | 61.98,56.43 R18.2 | 61.98,56.43 R10.2 R77.2
  Top 0.254: U1.A7 v38.73,46.99
  Route2 0.152: v38.73,46.99 v38.73,53.59
  Route15 0.152: v61.98,55.5 60.71,54.23 39.37,54.23 v38.73,53.59 36.45,53.59 v36.07,53.98
  Bottom 0.152: R73.2 v36.07,53.98
N$18  (via drill 0.25, 0.25 pad 0.61)
  Top 0.152: v34.92,55.37 34.04,55.37 R78.2 | R19.2 R78.2 | R11.2 R78.2
  Top 0.254: U1.D7 v42.55,46.99
  Route2 0.152: v42.55,46.99 v42.55,52.83 | v34.92,52.83 v34.92,55.37
  Route15 0.152: v42.55,52.83 v34.92,52.83
  Bottom 0.152: R73.1 35.39,56.86 34.92,56.39 v34.92,55.37
N$19  (via drill 0.25, 0.25 pad 0.61)
  Top 0.152: U1.G7 v47.62,46.99 | v34.04,30.48 34.04,29.97 34.29,29.72 R12.2 R20.2 R79.2
  Route2 0.152: v47.62,46.99 v47.62,51.44 v47.62,55.24 | v34.42,51.05 34.04,50.67 v34.04,30.48
  Route15 0.152: v47.62,51.44 34.8,51.44 v34.42,51.05
  Bottom 0.152: R68.2 47.66,55.28 v47.62,55.24
N$20  (via drill 0.25, 0.25 pad 0.61)
  Top 0.152: U1.J7 v50.16,46.99 | v58.17,30.23 57.15,30.23 R13.2 | R13.2 R21.2 | R80.2 R13.2
  Route2 0.152: v63.75,48.26 63.75,31.5 59.44,31.5 v58.17,30.23 | v50.16,46.99 v50.16,57.91
  Route15 0.152: v63.75,48.26 50.16,48.26 v50.16,46.99
  Bottom 0.152: v50.16,57.91 49.02,57.91 R68.1
N$27  (via drill 0.25 pad 0.61)
  Top 0.152: LED3.P v59.18,75.18
  Bottom 0.152: v59.18,75.18 59.18,73.28 R22.1
N$28  (via drill 0.25 pad 0.61)
  Top 0.152: LED2.P v33.53,75.18
  Bottom 0.152: v33.53,75.18 33.53,73.41 R23.1
N$30  (via drill 0.25 pad 0.61)
  Top 0.152: LED1.P v33.53,11.43
  Bottom 0.152: v33.53,11.43 33.53,13.21 R24.1
N$31  (via drill 0.25 pad 0.61)
  Top 0.152: LED0.P v59.05,11.43
  Bottom 0.152: v59.05,11.43 59.05,13.08 R25.1
N$32  (via drill 0.25 pad 0.61)
  Top 0.152: LED3.N v62.99,75.18
  Bottom 0.152: v62.99,75.18 62.99,71.12 M2.3
N$33  (via drill 0.25 pad 0.61)
  Top 0.152: LED2.N v29.59,75.18
  Bottom 0.152: v29.59,75.18 29.59,71.25 M3.3
N$34  (via drill 0.25 pad 0.61)
  Top 0.152: R31.1 79.41,65.44 79.12,65.79 v76.2,65.79
  Top 0.254: TP17.TP1 54.78,81.11 R59.2
  Route2 0.152: v76.2,65.79 76.2,70.48 76.33,70.61 76.33,75.95 70.99,75.95 64.14,82.8 57.91,82.8 TP17.TP1
N$35  (via drill 0.25 pad 0.61)
  Top 0.152: v77.85,62.23 R32.1
  Top 0.254: TP18.TP1 77.05,81.11 R60.2
  Route2 0.152: TP18.TP1 77.85,78.74 v77.85,62.23
N$36
  Bottom 0.152: U3.4 88.77,74.49 88.77,77.47 89.75,77.47 C45.2
N$37
  Bottom 0.152: JP7.3 72.14,28.07 73.15,29.12 C7.1
N$38  (via drill 0.25 pad 0.61)
  Top 0.152: R33.1 78.5,54.6 78.23,54.86 v78.23,55.12
  Top 0.254: TP19.TP1 37.43,80.86 R61.2
  Route2 0.152: v37.47,59.05 36.83,59.69 TP19.TP1
  Route15 0.152: v78.23,55.12 69.6,55.12 65.66,59.05 v37.47,59.05
N$39  (via drill 0.25 pad 0.61)
  Top 0.152: R34.1 79.38,51.82 v79.38,53.09
  Top 0.254: TP20.TP1 15.66,81.11 R62.2
  Route15 0.152: v79.38,53.09 78.87,53.09 77.6,54.36 69.34,54.36 65.23,58.47 24.82,58.47 20.07,63.25 20.07,75.31 16.51,78.87 TP20.TP1
N$40  (via drill 0.25 pad 0.61)
  Top 0.152: LED1.N v29.84,11.43
  Bottom 0.152: v29.84,11.43 29.84,15.24 M4.3
N$41  (via drill 0.25 pad 0.61)
  Top 0.152: LED0.N v62.99,11.43
  Bottom 0.152: v62.99,11.43 62.99,15.24 M5.3
N$42  (via drill 0.25, 0.25 pad 0.61)
  Top 0.152: U1.L6 v52.96,45.09
  Route2 0.152: v81.03,73.91 84.45,73.91 86.36,72.01 86.36,50.67 v85.72,50.04 | v72.9,49.15 v72.9,45.09
  Route15 0.152: v85.72,50.04 82.17,50.04 82.04,50.16 81.53,50.16 81.41,50.04 79.76,50.04 78.87,49.15 v72.9,49.15 | v72.9,45.09 v52.96,45.09
  Bottom 0.152: v81.03,73.91 81.03,75.06 R46.1 | JP8.1 69.85,51.44 69.85,49.15 v72.9,49.15
N$43  (via drill 0.25, 0.25 pad 0.61)
  Top 0.152: U1.H6 v48.9,45.72
  Route2 0.152: v48.9,45.72 49.53,46.61 v49.53,52.2 | v84.71,50.67 85.72,51.69 85.72,70.36 84.45,71.63 v81.03,71.63
  Route15 0.152: v49.53,52.2 v70.48,52.2 73.91,52.2 75.44,50.67 v84.71,50.67
  Bottom 0.152: v81.03,71.63 81.03,72.64 R45.1 | JP8.2 70.48,52.7 v70.48,52.2
N$44  (via drill 0.25, 0.25 pad 0.61)
  Top 0.152: R35.1 v77.98,26.42
  Top 0.254: TP21.TP1 37.68,5.25 R63.2
  Route2 0.152: v77.98,26.42 77.22,25.65 77.22,7.87 78.23,6.86 v78.23,3.17
  Route15 0.152: v78.23,3.17 77.85,3.05 39.37,3.05 TP21.TP1
N$45  (via drill 0.25 pad 0.61)
  Top 0.152: v78.99,22.35 79.39,22.63 79.39,23.02 79.4,23.14 R36.1
  Top 0.254: TP22.TP1 15.66,5.25 R64.2
  Route2 0.152: v78.99,2.54 v78.99,22.35
  Route15 0.152: TP22.TP1 20.07,2.54 v78.99,2.54
N$46
  Bottom 0.305: JP4.3 70.9,16.73 70.74,16.89 R42.2
N$47
  Bottom 0.305: JP3.3 19.78,16.73 19.94,16.89 R41.2
N$48  (via drill 0.25 pad 0.61)
  Top 0.152: v78.36,13.72 R37.1
  Top 0.254: TP23.TP1 55.03,5.25 R65.2
  Route15 0.152: TP23.TP1 58.42,3.56 73.79,3.56 73.79,7.37 76.71,10.29 76.71,13.72 v78.36,13.72
N$49
  Top 0.152: R38.1 78.11,11.18 76.2,9.27 TP24.TP1
  Top 0.254: TP24.TP1 77.05,5.25 R66.2
N$50
  Bottom 0.305: R40.2 19.27,72.51 JP2.3
N$51
  Bottom 0.305: JP1.3 71.66,72.01 R39.2
N$52  (via drill 0.25, 0.25 pad 0.61)
  Top 0.152: U1.E6 v43.81,45.72
  Route2 0.152: v43.81,45.72 U1.E6 50.42,45.09 50.8,45.47 v50.8,50.29 | v74.42,50.29 74.42,54.74 73.79,55.37 73.79,56.52 74.42,57.15 v74.42,68.96
  Route15 0.152: v50.8,50.29 v74.42,50.29 | v74.42,68.96 v81.03,68.96
  Bottom 0.152: R44.1 81.03,70.1 v81.03,68.96 | JP8.3 71.25,53.98 71.25,50.29 v74.42,50.29
N$53  (via drill 0.25, 0.25 pad 0.61)
  Top 0.152: U1.B6 v40.01,45.72
  Route2 0.152: v40.01,45.72 39.37,46.35 v39.37,60.33 | v66.04,55.24 66.04,65.66 v66.8,66.42
  Route15 0.152: v39.37,60.33 44.58,60.33 50.93,66.67 65.91,66.67 66.17,66.42 v66.8,66.42 v78.74,66.42
  Bottom 0.152: v78.74,66.42 79.25,66.42 79.63,66.8 79.63,67.56 R43.1 | JP8.4 v66.04,55.24
N$58  (via drill 0.25)
  Top 0.152: U1.F3 v46.35,41.91
  Route2 0.152: v46.35,41.91 45.34,40.89 43.18,40.89 43.18,38.48 v42.16,37.34
  Bottom 0.152: v42.16,37.34 41.53,37.34 R52.1
N$59
  Bottom 0.152: R54.2 R53.1 16.26,63.21 JP5.1
N$60
  Bottom 0.152: R56.2 R55.1 17.6,23.33 JP6.1
N$61
  Bottom 0.152: JP7.1 73.03,21.88 73.28,22.23 73.28,23.11 73.83,23.11 R57.1 R58.2
PG0  (via drill 0.25, 0.25 pad 0.61)
  Top 0.152: J3.9 97.79,18.54 91.44,18.54 J4.9 | U1.J2 v48.9,39.37 | R26.R4_1 77.98,56.87 v77.98,56.39
  Route2 0.152: v48.9,39.37 48.9,24.51 v59.05,14.61 | v77.72,39.37 77.72,54.74 77.6,54.86 77.6,56.01 v77.98,56.39
  Route15 0.152: v59.05,14.61 64.64,14.61 65.41,13.84 73.15,13.84 74.04,14.73 82.68,14.73 87.76,19.81 J4.9 | v48.9,39.37 v77.72,39.37
  Bottom 0.152: M5.1 v59.05,14.61
PG1  (via drill 0.25, 0.25 pad 0.61)
  Top 0.152: J3.21 97.79,33.78 91.44,33.78 J4.21 | U1.F2 v45.09,39.37 | R26.R3_1 80.26,57.77 v80.26,53.47
  Route2 0.152: v32.64,18.8 45.09,31.24 v45.09,39.37 46.23,40.51 59.44,40.51 v59.94,41.02 | v80.26,53.47 80.26,42.93 v78.49,41.02
  Route15 0.152: v32.64,18.8 v32.64,16.89 | v59.94,41.02 v78.49,41.02 78.49,38.23 80.26,36.45 88.77,36.45 J4.21
  Bottom 0.152: v32.64,16.89 32.62,16.88 M4.1
PG2  (via drill 0.25 pad 0.61)
  Top 0.152: J3.35 97.79,51.56 91.44,51.56 J4.35 | U1.C2 v41.27,39.37 | R26.R2_1 79.27,58.55 v75.95,58.55
  Route2 0.152: v41.27,39.37 39.5,37.59 v36.32,37.59 | v30.23,64.52 v30.23,41.15 | v75.95,36.83 75.95,42.8 76.07,42.93 76.07,43.31 75.95,43.43 v75.95,58.55
  Route15 0.152: v30.23,41.15 33.78,37.59 v36.32,37.59 | J4.35 88.52,52.83 83.57,57.91 76.58,57.91 v75.95,58.55 | v41.27,39.37 43.81,36.83 v75.95,36.83
  Bottom 0.152: M3.1 31.77,71.9 31.5,71.63 31.5,64.52 v30.23,64.52
PG3  (via drill 0.25, 0.25 pad 0.61)
  Top 0.152: U1.C3 v42.55,41.91 | J3.47 97.79,66.8 91.44,66.8 J4.47 | v77.85,61.09 78.61,61.09 79.25,60.45 79.25,59.5 R26.R1_1
  Route2 0.152: v42.55,41.91 38.99,38.35 v37.08,38.35 | v32.51,67.31 32.51,61.72 30.99,60.2 v30.99,41.15
  Route15 0.152: v58.93,70.48 35.43,70.48 v32.51,67.31 | v30.99,41.15 33.78,38.35 v37.08,38.35 | v62.23,65.79 65.91,65.79 66.17,65.53 67.44,65.53 67.69,65.79 72.64,65.79 77.34,61.09 v77.85,61.09 87.88,61.09 87.88,68.07 J4.47
  Bottom 0.152: v58.93,70.48 58.94,70.47 M2.1 60.21,68.98 62.23,66.93 v62.23,65.79
RUN_CH0  (via drill 0.25, 0.25 pad 0.61)
  Top 0.152: U1.K7 v51.44,46.99 | v82.68,33.66 82.68,32.51 R9.1
  Route2 0.152: v82.68,33.66 86.36,33.66 | 86.36,33.66 88.39,31.24 94.23,31.24 94.23,23.88 J4.12 | v55.63,57.91 v55.63,47.62 | v87.63,48.01 87.63,34.92 86.36,33.66
  Route15 0.152: v51.44,46.99 51.44,47.62 v55.63,47.62 65.02,47.62 65.41,48.01 v87.63,48.01
  Bottom 0.152: J3.12 100.33,21.08 93.98,21.08 J4.12 | v55.63,57.91 56.64,57.91 R71.1
RUN_CH1  (via drill 0.25, 0.25 pad 0.61)
  Top 0.152: U1.J6 v50.16,45.72 | J4.24 91.44,36.32 86.36,36.32 86.36,31.24 80.77,31.24 80.77,35.05 | 80.77,35.05 R8.1 | 80.77,35.05 73.79,35.05 v73.79,45.72
  Route2 0.152: v58.04,54.86 v58.04,45.72
  Route15 0.152: v50.16,45.72 50.8,45.09 52.07,45.09 52.7,45.72 v58.04,45.72 v73.79,45.72
  Bottom 0.152: J3.24 100.33,36.32 93.98,36.32 J4.24 | R71.2 57.66,55.28 v58.04,54.86
RUN_CH2  (via drill 0.25, 0.25 pad 0.61)
  Top 0.152: U1.F6 v46.35,45.72 | v80.39,39.24 80.39,38.35 80.9,37.85 R7.1
  Route2 0.152: v46.35,45.72 46.35,56.77 v45.72,57.4
  Route15 0.152: v46.35,45.72 48.26,43.81 80.39,43.81 | v80.39,39.24 80.39,43.81 | 80.39,43.81 88.52,43.81 89.15,43.94 99.44,43.94 100.46,44.96 100.46,54.23 J3.38
  Bottom 0.152: J3.38 100.33,54.1 93.98,54.1 J4.38 | v45.72,57.4 43.81,57.4 43.31,56.9 42.2,56.9 R76.1
RUN_CH3  (via drill 0.25)
  Top 0.152: U1.C6 v41.27,45.72 | v81.79,49.53 R6.1
  Route15 0.152: J3.50 100.08,69.09 100.08,49.02 85.6,49.02 85.09,49.53 v81.79,49.53 80.01,49.53 78.99,48.51 65.41,48.51 65.02,48.9 42.93,48.9 41.91,48.01 41.91,46.35 v41.27,45.72
  Bottom 0.152: J3.50 100.33,69.34 93.98,69.34 J4.50 | R76.2 42.16,54.36 41.99,54.23 41.99,51.56 42.42,51.18 42.42,48.01 41.91,47.62 41.91,46.35 v41.27,45.72
TRACK0  (via drill 0.25, 0.25 pad 0.61)
  Top 0.152: U1.K6 v51.44,45.72
  Route2 0.152: v68.83,46.35 68.83,25.27 TP16.1 JP7.2 | v54.1,46.35 54.1,47.75 52.07,47.75 | v51.44,45.72 52.07,46.35 52.07,47.75 | 52.07,47.75 51.56,48.26 51.56,56.64 v52.83,57.91
  Route15 0.152: v54.1,46.35 v68.83,46.35
  Bottom 0.152: v52.83,57.91 51.56,57.91 R69.1
TRACK1  (via drill 0.25 pad 0.61)
  Top 0.152: U1.G6 v46.35,44.45
  Route2 0.152: JP6.2 TP15.1 33.78,24.13 34.92,25.27 34.92,28.19 35.31,28.57 35.31,43.81 41.27,43.81 41.91,44.45 v46.35,44.45 43.18,44.45 43.18,46.23 43.94,46.99 43.94,47.62 44.2,47.88 44.2,57.66 44.7,58.17 46.35,58.17 46.99,57.53 v46.99,56.01
  Bottom 0.152: v46.99,56.01 46.99,56.13 50.42,56.13 50.42,55.24 51.56,55.24 R69.2
TRACK2  (via drill 0.25, 0.25 pad 0.61)
  Top 0.152: U1.D6 v42.55,45.72
  Route2 0.152: v42.55,45.72 41.91,46.35 v41.91,57.91
  Route15 0.152: JP5.2 TP14.1 23.62,57.91 v38.1,57.91 v41.91,57.91
  Bottom 0.152: R74.1 v38.1,57.91
TRACK3  (via drill 0.25)
  Top 0.152: U1.A6 v38.73,45.72
  Bottom 0.152: v38.73,45.72 38.1,46.35 38.1,49.4 | 38.1,49.4 R74.2 | C4.1 38.14,49.44 38.1,49.4
TSENSE0P  (via drill 0.25 pad 0.61)
  Route2 0.152: J3.46 102.87,64.26 102.87,51.56 J3.34 102.87,49.02 102.87,33.78 J3.20 102.87,31.24 102.87,18.54 J3.8
  Route15 0.152: v56.52,34.16 77.98,34.16 81.28,30.86 89.03,30.86 89.41,31.24 91.44,31.24 J4.20
  Bottom 0.152: J3.8 100.33,16 93.98,16 J4.8 | J3.20 100.33,31.24 93.98,31.24 J4.20 | J3.46 100.33,64.26 93.98,64.26 J4.46 | J3.34 100.33,49.02 93.98,49.02 J4.34 | v56.52,34.16 55.88,34.16 55.63,34.42 R52.2 C20.1 39.71,36.17 Q1.1 39.73,37.34 38.73,37.34 Q1.3
VDAC0  (via drill 0.25, 0.25 pad 0.61)
  Top 0.152: R21.1 60.96,26.16 61.34,25.78 v61.72,25.78
  Route2 0.152: v61.72,25.78 65.66,25.78 71.88,19.56 v74.42,19.56
  Route15 0.152: v74.42,19.56 86.23,19.56 88.01,21.08 91.44,21.08 J4.10
  Bottom 0.152: J3.10 100.33,18.54 93.98,18.54 J4.10
VDAC1  (via drill 0.25, 0.25 pad 0.61)
  Top 0.152: v35.94,27.94 30.31,27.94 R20.1
  Route2 0.152: v35.94,27.94 36.58,27.94 v42.04,33.02
  Route15 0.152: J4.22 91.44,33.78 89.53,33.78 88.52,34.8 43.81,34.8 v42.04,33.02
  Bottom 0.152: J3.22 100.33,33.78 93.98,33.78 J4.22
VDAC2  (via drill 0.25 pad 0.61)
  Top 0.152: R19.1 v32,59.18
  Route15 0.152: v32,59.18 32.64,59.82 34.42,59.82 34.54,59.69 54.48,59.69 54.61,59.56 75.95,59.56 76.58,59.05 76.58,58.67 76.96,58.29 84.33,58.29 88.52,54.1 91.44,54.1 J4.36
  Bottom 0.152: J3.36 100.33,51.56 93.98,51.56 J4.36
VDAC3  (via drill 0.25 pad 0.61)
  Top 0.152: R18.1 64.81,58.13 v65.28,57.66
  Route15 0.152: v65.28,57.66 68.96,53.98 77.09,53.98 79.38,51.56 93.6,51.56 94.49,52.58 94.49,66.29 J4.48
  Bottom 0.152: J3.48 100.33,66.8 93.98,66.8 J4.48
VIN  (via drill 0.25)
  Top 0.152: v13.34,47.88
  Top 0.406: C3.1 v13.34,47.88
  Route2 0.152: v13.59,39.75 12.83,40.51 12.83,43.43 v12.32,43.94 | J4.6 95.25,17.27 95.25,38.1 J4.26 | v91.44,72.39 91.44,41.91 J4.25
  Bottom 0.152: U2.7 13.9,39.44 v13.59,39.75 | v12.32,43.94 13.59,43.94 R1.I2 14.5,44.2 16.51,44.2 16.76,43.94 | v13.34,47.88 13.4,47.88 | J3.6 100.33,13.46 93.98,13.46 J4.6 | U3.1 91.31,76.39 91.31,74.42 90.29,74.42 U3.3 90.3,73.53 v91.44,72.39
  Bottom 0.203: 16.76,43.94 16.76,41.15
  Bottom 0.254: 13.4,47.88 M1.5 | 16.76,41.15 26.16,31.75 72.77,31.75 76.83,35.81 87.12,35.81 87.12,37.59 J4.25
  Bottom 0.406: J3.26 J3.25 J4.26 J4.25
  pour Bottom: 8.89,49.15 10.92,49.15 12.06,50.42 12.19,50.55 16.64,50.55 16.64,42.93 8.89,42.93
VIN_U1  (via drill 0.25, 0.25 pad 0.61)
  Top 0.152: 52.07,43.05 | U1.B4 41.15,42.04 v41.15,41.91 | v51.56,41.91 52.07,41.91 52.07,43.05 | 52.07,43.05 C47.1
  Top 0.254: U1.B4 U1.B5 | v41.15,41.91 40.64,42.42 U1.B4 | U1.B4 40.64,41.91 | 40.64,41.91 U1.B3 40.64,41.4 v41.15,41.91 | 44.45,41.4 v44.96,41.91 44.45,42.42 | U1.E4 44.45,42.42 | 44.45,42.42 v43.94,41.91 44.45,41.4 | 44.45,41.4 U1.E3 | 48.26,42.42 v48.77,41.91 48.26,41.4 | U1.H4 48.26,42.42 | 48.26,42.42 v47.75,41.91 48.26,41.4 | U1.H3 48.26,41.4 | 52.07,41.4 v52.58,41.91 52.07,42.42 | U1.L3 52.07,41.4 | 52.07,41.4 v51.56,41.91 52.07,42.42 | U1.L4 52.07,42.42 | v41.15,41.91 40.64,41.91
  Top 0.356: U1.H4 U1.H5
  Top 0.406: U1.E5 U1.E4 U1.E3 | U1.H3 U1.H4 | 52.07,41.15 U1.L3 U1.L4 52.07,43.05 U1.L5
  Bottom 0.152: v41.15,41.91 25.4,41.91 21.08,46.23 19.48,46.23 | C48.1 54.99,42.93 53.98,41.91 v52.58,41.91
  Bottom 0.229: v44.96,41.91 45.47,42.55 47.24,42.55 v47.75,41.91 | v43.94,41.91 43.31,42.55 41.78,42.55 v41.15,41.91
  pour Bottom: 38.35,44.45 58.93,44.45 58.93,40.64 38.86,40.64 36.07,37.85 20.57,37.85 17.14,41.15 17.14,47.75 34.8,47.75
VSNSM_CH0
  Top 0.152: J3.1 97.79,8.38 91.44,8.38 J4.1 83.19,9.65 82.33,10.5 82.33,11.14 82.3,11.18 | R38.2 82.3,11.18 | 82.3,11.18 C44.1
VSNSM_CH1
  Top 0.152: J3.13 97.79,23.62 91.44,23.62 J4.13 82.68,24.89 82.3,24.51 82.3,23.88 | R36.2 82.3,23.88 | 82.3,23.88 C42.1 83.44,23.91
VSNSM_CH2
  Top 0.152: J3.27 97.79,41.4 91.44,41.4 J4.27 88.27,42.67 88.27,51.82 87,53.09 83.95,53.09 83.57,52.7 83.57,51.73 C40.1 R34.2
VSNSM_CH3
  Top 0.152: J3.39 97.79,56.64 91.44,56.64 J4.39 89.15,57.91 88.14,58.8 88.14,63.25 83.82,63.25 83.48,62.99 C38.1 R32.2
VSNSP_CH0
  Top 0.152: R37.2 82.3,13.72 | 82.3,13.72 C43.1 | J4.2 91.44,10.92 89.28,10.92 87.88,12.32 82.8,12.32 82.33,12.79 82.33,13.68 82.3,13.72
  Bottom 0.152: J3.2 100.33,8.38 93.98,8.38 J4.2
VSNSP_CH1
  Top 0.152: R35.2 82.3,26.42 | 82.3,26.42 C41.1 83.57,26.33 | J4.14 91.69,24.89 90.55,26.04 89.66,26.04 88.9,25.4 82.68,25.4 82.3,25.78 82.3,26.42
  Bottom 0.152: J3.14 100.33,23.62 93.98,23.62 J4.14
VSNSP_CH2
  Top 0.152: R33.2 C39.1 83.57,54.65 83.57,53.98 83.95,53.59 87.25,53.59 88.77,52.07 88.77,43.94 90.55,43.94 91.82,43.18 J4.28
  Bottom 0.152: J3.28 100.33,41.4 93.98,41.4 J4.28
VSNSP_CH3
  Top 0.152: R31.2 C37.1 83.48,64.01 83.82,63.75 88.65,63.75 88.65,59.31 88.77,59.18 90.42,59.18 91.69,57.91 J4.40
  Bottom 0.152: J3.40 100.33,56.64 93.98,56.64 J4.40
(copper drawn outside any net)
  shapes: Top area x1

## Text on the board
tPlace: GND | 2.5V | 3.3V | GND | 4.5V-14V | SNS- | SNS+ | SNS+ | SNS- | 4A | 4A | ON | ON | OFF | 50 | OFF | 47 | PRE-LOAD | PRE-LOAD | 46 | 43 | TRK | 42 | TRACK2 | SS | 39 | CH2 | CH3 | 38 | 35 | LTM4644 QUAD 4A POWER SUPPLY with | +VIN | 50-PIN CONNECTOR to Power System Manager | 34 | 31 | 30 | 27 | (408) 432-1900 | 26 | www.linear.com | 23 | 22 | DEMO CIRCUIT 2363A | 19 | 18 | CH1 | CH0 | 15 | SS | GND | SS | 14 | TRK | 11 | TRACK1 | TRK | TRACK0 | 10 | 7 | CLKIN | ON | ON | OFF | 6 | OFF | 3 | PRE-LOAD | CLKOUT | PRE-LOAD | 4A | 4A | SNS- | SNS+ | SNS+ | SNS- | GND | 1.5V | 1.0V | GND
bPlace: 1a | mtp | Rev | 49 | 48 | 45 | 44 | 41 | 40 | 37 | 36 | 33 | CCM | DCM | 32 | 29 | 28 | 25 | 24 | 21 | 20 | 17 | 16 | 13 | LTC CONFIDENTIAL | 12 | 9 | FOR CUSTOMER USE ONLY | 8 | 5 | 4 | 1
d_FabDrawing: 3.40" | 0.00" | 0.00" | 4.10"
